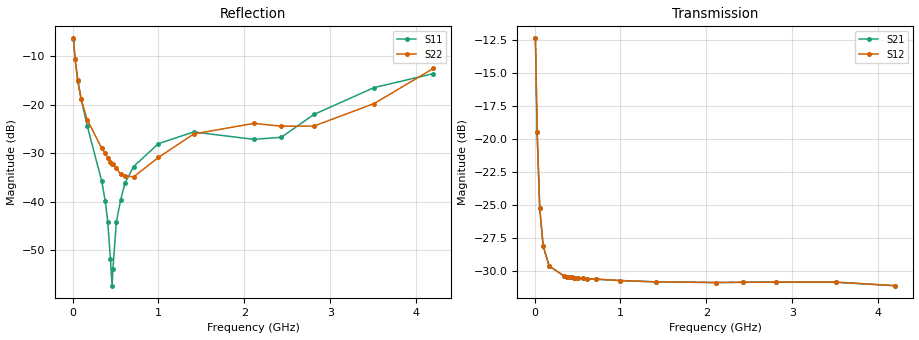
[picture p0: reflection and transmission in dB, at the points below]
! Integrated Device Technology
! Corporate Headquarters
! 6024 Silver Creek Valley Road
! San Jose, CA 95138  USA
! Phone:  1-408-284-8200
! Toll Free:  1-800-223-1366
! Webpage:  http://www.idt.com/
! Timing and RF Division
! 515 Groton Road, Suite 102
! Westford, MA 01886-6024
! Device:  F1950
! Description: 7-bit 0.25 dB Digital Step Attenuator
! Frequency:  150.0 -  4000.00 MHz
! Package:  4x4 mm Thin QFN Plastic Package: 24 pin
! Ports:  2 RF, 12 DC
!  Pin  1  = D0
!  Pin  2  = VDD
!  Pin  3  = Vmode
!  Pin  4  = GND
!  Pin  5  = RF1  =  Port 1
!  Pin  6  = GND
!  Pin  7  = GND
!  Pin  8  = GND
!  Pin  9  = GND
!  Pin 10  = GND
!  Pin 11  = GND
!  Pin 12  = GND
!  Pin 13  = GND
!  Pin 14  = RF2  =  Port 2
!  Pin 15  = GND
!  Pin 16  = LE
!  Pin 17  = CLK
!  Pin 18  = DATE
!  Pin 19  = D6
!  Pin 20  = D5
!  Pin 21  = D4
!  Pin 22  = D3
!  Pin 23  = D2
!  Pin 24  = D1
! State:  119
! Atten State:  29.75 dB
! Voltage:  +5.00 Volts
! Current:  Not Measured mA
! Data:  The device was measured on a the F195X evaluation board which has
!  individual transmission lines to the RF pins.  Data was collected
!  using a calibrated network analyzer.  The evaluation board was
!  de-embedded using a TRL calibration technique.
!  The reference plane is the edge of the package pin.
! Misc:  Board 2019
!  Action Tracker AT0250
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# GHz S dB R 50
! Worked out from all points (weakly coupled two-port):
!   420 points, 10 MHz to 4.2 GHz, reference 50 ohm
!   highest |S21| = -12.40 dB at 10 MHz (marker M1); lowest = -31.1 dB at 4.2 GHz (marker M2)
!   lowest |S11| = -57.3 dB at 460 MHz (marker M3), VSWR 1.00, Z = 49.9 - j0.0328 ohm
!   |S11| at or under -10 dB: 26.65 MHz to end of sweep
!   |S22| runs from -35.2 to -6.3 dB; largest |S21 - S12| = 8.5e-05
!   S11 on the Smith chart (normalised r, x): 10 MHz: 1.97, -1.17; 30 MHz: 1.28, -0.64; 60 MHz: 1.11, -0.36; 410 MHz: 1.00, -0.01; 4.2 GHz: 0.69, +0.17
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0.01  -6.45 -28.9  -12.40 -42.2  -12.39 -42.1  -6.29 -29.4
0.03  -10.64 -50.8  -19.49 -62.6  -19.49 -62.6  -10.50 -52.6
0.06  -15.03 -63.5  -25.22 -56.0  -25.22 -56.0  -14.78 -65.4
0.1  -18.89 -70.3  -28.11 -42.2  -28.11 -42.2  -18.86 -70.9
0.17  -24.28 -71.8  -29.63 -28.5  -29.63 -28.5  -23.07 -76.7
0.34  -35.78 -69.9  -30.37 -17.2  -30.37 -17.2  -28.96 -85.4
0.38  -39.82 -69.6  -30.43 -16.1  -30.43 -16.1  -30.00 -87.0
0.41  -44.16 -76.1  -30.46 -15.5  -30.46 -15.5  -30.89 -88.5
0.44  -51.75 -95.2  -30.49 -15.0  -30.48 -15.0  -31.71 -92.7
0.46  -57.28 -166.1  -30.50 -14.7  -30.50 -14.7  -32.12 -96.1
0.47  -53.76 157.6  -30.51 -14.6  -30.51 -14.6  -32.28 -97.7
0.51  -44.09 137.0  -30.53 -14.1  -30.54 -14.1  -32.97 -101.9
0.56  -39.56 133.6  -30.56 -13.7  -30.56 -13.8  -34.35 -110.1
0.61  -36.15 134.9  -30.59 -13.4  -30.58 -13.5  -34.63 -121.2
0.71  -32.72 136.6  -30.63 -13.2  -30.62 -13.2  -34.85 -141.2
1  -27.99 146.8  -30.73 -13.7  -30.73 -13.7  -30.83 177.8
1.41  -25.59 161.7  -30.83 -15.3  -30.83 -15.3  -26.01 159.5
2.11  -27.11 155.8  -30.88 -19.5  -30.88 -19.5  -23.82 141.1
2.43  -26.68 124.0  -30.86 -21.2  -30.86 -21.2  -24.40 130.1
2.81  -21.97 103.9  -30.86 -24.2  -30.85 -24.2  -24.37 114.6
3.51  -16.44 116.4  -30.86 -29.0  -30.85 -29.1  -19.73 112.3
4.2  -13.57 145.0  -31.12 -31.3  -31.12 -31.4  -12.49 126.7
